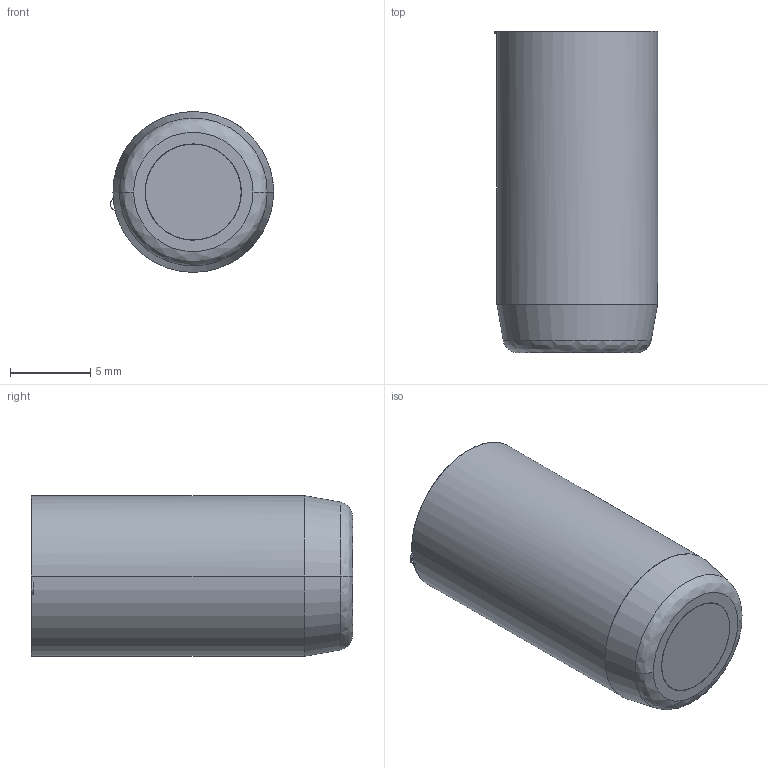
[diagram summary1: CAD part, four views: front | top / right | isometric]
IGES file: header records copied from the file, then geometry measured from it (millimetres).
Start section: START RECORD GO HERE.
Global section: file name: fa105712-20.igs; native system: DASSAULT SYSTEMES CATIA V5 R20 - www.3ds.com; preprocessor: CATIA Version 5 Release 20 ; author: Utente; organization: NB04-ASUS; date: 20201108.083649; units: millimetre
Bounding box: 10.15 x 20 x 10 mm (x, y, z)
Surface area: 1742 mm2 (no closed solid volume)
Topology: 0 solids, 0 shells, 422 faces, 2085 edges, 2074 vertices
Faces by surface type: revolution 195, plane 151, bspline 76
